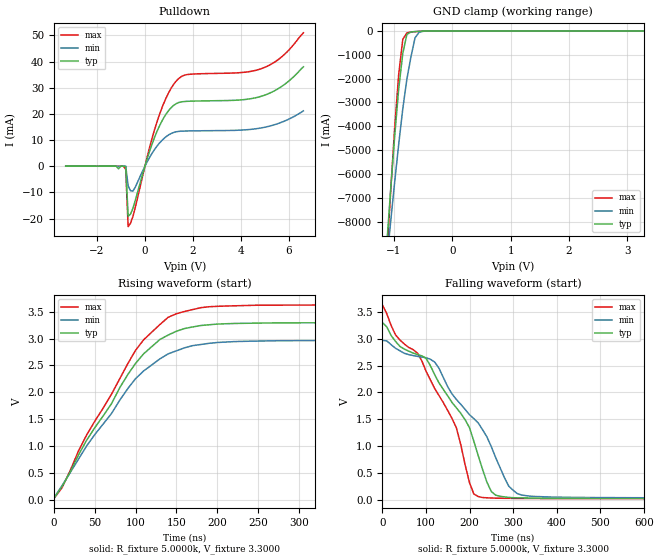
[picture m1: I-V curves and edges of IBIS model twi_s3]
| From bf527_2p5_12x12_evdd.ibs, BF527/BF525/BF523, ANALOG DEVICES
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|   Model ptwi400kv123
[Model]   twi_s3
Model_type I/O_open_drain
Polarity   Non-Inverting
Enable   Active-Low
Vinl =   0.9900V
Vinh =   2.3100V
Vmeas =  1.6500V
Cref =   50.0000pF
Rref =   5.0000k
Vref =   3.3000V
C_comp   7.1300pF   6.4200pF   7.8500pF
[Temperature Range]   25.0000   0.1250k   0.0
[Voltage Range]   3.3000V   2.9700V   3.6300V
[Pullup Reference]   3.3000V   2.9700V   3.6300V
[Pulldown Reference]   0.0V   0.0V   0.0V
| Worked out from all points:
|   slope of the pulldown table from 0 to 0.495 V, typ, clamps not added: 37.7 ohm
|   GND clamp passes 1 mA (typ) near -0.44 V on its own axis
|   rising waveform, R_fixture 5.0000k, V_fixture 3.3000: 20-80 % time 80.6ns typ, 84.1ns min, 80.7ns max; typ from 0.021 V to 3.3 V
|   falling waveform, R_fixture 5.0000k, V_fixture 3.3000: 20-80 % time 127ns typ, 135ns min, 138ns max; typ from 3.3 V to 0.021 V
[Pulldown]
|Voltage   I(typ)   I(min)   I(max)
-3.3V     0A         0A         0A
-900mV    0A         0A         0A
-800mV    -100uA     0A         -1.16mA
-700mV    -19.11mA   -7.5mA     -23.08mA
-500mV    -16.06mA   -9.49mA    -19.19mA
500mV     13.25mA    7.66mA     16.88mA
900mV     20.2mA     11.43mA    26.48mA
1.3V      23.91mA    13.17mA    32.53mA
1.8V      24.83mA    13.48mA    35.09mA
4.9V      26.9mA     14.74mA    37.48mA
5.7V      30.53mA    16.84mA    41.86mA
6.6V      38mA       21.16mA    51mA
[GND_clamp]
|Voltage   I(typ)   I(min)   I(max)
-3.3V     -90.22A    -67.03A    -109.2A
-1.13V    -9.149A    -9.8A      -9.77A
-1.06V    -6.738A    -8.067A    -6.84A
-990mV    -4.45A     -6.376A    -4.101A
-920mV    -2.435A    -4.756A    -1.825A
-850mV    -942.6mA   -3.267A    -350.3mA
-780mV    -143.7mA   -2.02A     -77.09mA
-710mV    -40.25mA   -1.083A    -45.36mA
-640mV    -20.51mA   -284.6mA   -28.77mA
-570mV    -9.991mA   -53.76mA   -15.59mA
-500mV    -3.489mA   -11.54mA   -6.229mA
3.28V     9.245nA    33.22nA    22.11nA
[Ramp]
| variable   typ   min   max
dV/dt_r  1.9668/80.8522n   1.7623/84.3593n   2.1657/80.9872n
dV/dt_f  1.9673/0.1273u   1.7618/0.1350u   2.1662/0.1385u
R_load = 5.0000k
[Rising Waveform]
R_fixture= 5.0000k
V_fixture= 3.3000
V_fixture_min= 2.9700
V_fixture_max= 3.6300
L_fixture= 0.0H
C_fixture= 0.0F
|time   V(typ)   V(min)   V(max)
0s        20.94mV    31.89mV    18.58mV
10.1ns    246.2mV    262.5mV    224.4mV
40.4ns    1.114V     1.007V     1.212V
100ns     2.538V     2.254V     2.782V
130ns     2.986V     2.625V     3.265V
140ns     3.067V     2.717V     3.398V
160ns     3.188V     2.829V     3.506V
190ns     3.258V     2.913V     3.594V
280ns     3.294V     2.962V     3.624V
1us       3.299V     2.969V     3.628V
[Falling Waveform]
R_fixture= 5.0000k
V_fixture= 3.3000
V_fixture_min= 2.9700
V_fixture_max= 3.6300
L_fixture= 0.0H
C_fixture= 0.0F
|time   V(typ)   V(min)   V(max)
0s        3.3V       2.969V     3.629V
30.3ns    2.948V     2.821V     3.07V
120ns     2.331V     2.565V     2.074V
160ns     1.81V      1.969V     1.511V
200ns     1.341V     1.583V     314.6mV
220ns     821.3mV    1.431V     58.01mV
250ns     152.2mV    987.7mV    31.92mV
290ns     42.14mV    253mV      25.46mV
320ns     33.15mV    86.25mV    23.15mV
1us       21.19mV    32.72mV    18.68mV
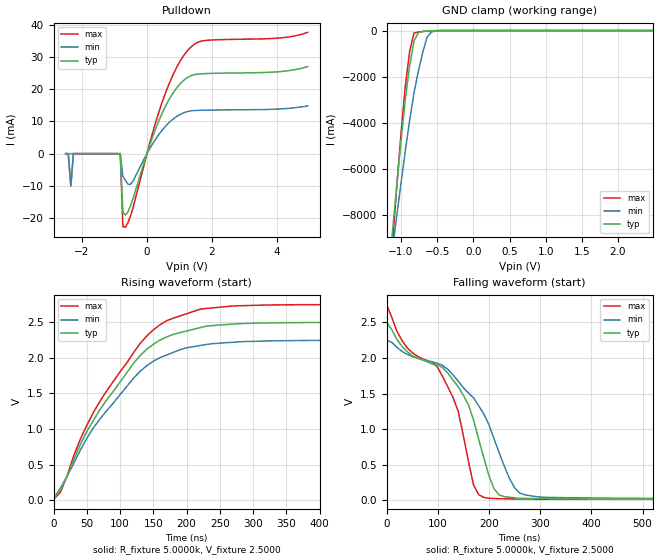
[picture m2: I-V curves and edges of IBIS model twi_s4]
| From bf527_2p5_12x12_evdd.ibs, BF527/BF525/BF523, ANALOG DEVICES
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[Model]   twi_s4
Model_type I/O_open_drain
Polarity   Non-Inverting
Enable   Active-Low
Vinl =   0.7500V
Vinh =   1.7500V
Vmeas =  1.2500V
Cref =   50.0000pF
Rref =   5.0000k
Vref =   2.5000V
C_comp   7.1300pF   6.4200pF   7.8500pF
[Temperature Range]   25.0000   0.1250k   0.0
[Voltage Range]   2.5000V   2.2500V   2.7500V
[Pullup Reference]   2.5000V   2.2500V   2.7500V
[Pulldown Reference]   0.0V   0.0V   0.0V
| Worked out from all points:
|   slope of the pulldown table from 0 to 0.375 V, typ, clamps not added: 36 ohm
|   GND clamp passes 1 mA (typ) near -0.43 V on its own axis
|   rising waveform, R_fixture 5.0000k, V_fixture 2.5000: 20-80 % time 99.5ns typ, 102ns min, 102ns max; typ from 0.016 V to 2.5 V
|   falling waveform, R_fixture 5.0000k, V_fixture 2.5000: 20-80 % time 134ns typ, 106ns min, 125ns max; typ from 2.5 V to 0.016 V
[Pulldown]
|Voltage   I(typ)   I(min)   I(max)
-2.5V     0A         0A         0A
-2.42V    0A         0A         0A
-2.34V    0A         -10mA      -10mA
-2.26V    0A         0A         0A
-820mV    0A         0A         -100uA
-740mV    -18.24mA   -7mA       -22.61mA
-660mV    -19.07mA   -8.3mA     -22.8mA
-500mV    -16.06mA   -9.49mA    -19.19mA
460mV     12.37mA    7.169mA    15.73mA
1.26V     23.69mA    13.08mA    32.09mA
1.74V     24.8mA     13.47mA    35.01mA
4.94V     27.02mA    14.81mA    37.62mA
[GND_clamp]
|Voltage   I(typ)   I(min)   I(max)
-2.5V     -59.97A    -45.67A    -72.09A
-1.12V    -8.799A    -9.551A    -9.345A
-1.06V    -6.738A    -8.067A    -6.84A
-1V       -4.765A    -6.614A    -4.473A
-940mV    -2.968A    -5.209A    -2.401A
-880mV    -1.51A     -3.883A    -891.6mA
-820mV    -449.6mA   -2.695A    -106.2mA
-760mV    -91.03mA   -1.757A    -63.86mA
-640mV    -20.51mA   -284.6mA   -28.77mA
-580mV    -11.24mA   -67.34mA   -17.26mA
-520mV    -4.937mA   -17.93mA   -8.448mA
2.48V     854.5pA    19.73nA    1.171nA
[Ramp]
| variable   typ   min   max
dV/dt_r  1.4899/99.7831n   1.3349/0.1019u   1.6410/0.1023u
dV/dt_f  1.4904/0.1344u   1.3346/0.1063u   1.6415/0.1257u
R_load = 5.0000k
[Rising Waveform]
R_fixture= 5.0000k
V_fixture= 2.5000
V_fixture_min= 2.2500
V_fixture_max= 2.7500
L_fixture= 0.0H
C_fixture= 0.0F
|time   V(typ)   V(min)   V(max)
0s        15.84mV    24.09mV    14.05mV
10.1ns    137.6mV    167.7mV    109.1mV
40.4ns    784.7mV    707.3mV    861.3mV
60.61ns   1.132V     1.027V     1.245V
130ns     2.031V     1.811V     2.201V
150ns     2.19V      1.953V     2.394V
170ns     2.294V     2.04V      2.522V
220ns     2.423V     2.173V     2.682V
350ns     2.494V     2.241V     2.745V
1us       2.499V     2.249V     2.749V
[Falling Waveform]
R_fixture= 5.0000k
V_fixture= 2.5000
V_fixture_min= 2.2500
V_fixture_max= 2.7500
L_fixture= 0.0H
C_fixture= 0.0F
|time   V(typ)   V(min)   V(max)
0s        2.5V       2.249V     2.75V
40.4ns    2.088V     2.051V     2.141V
90.91ns   1.91V      1.941V     1.936V
120ns     1.784V     1.837V     1.59V
140ns     1.596V     1.674V     1.25V
170ns     1.129V     1.439V     212.9mV
190ns     595.7mV    1.214V     40.34mV
220ns     75.56mV    667.9mV    23.3mV
270ns     26.68mV    78.13mV    18.21mV
1us       15.99mV    24.66mV    14.12mV
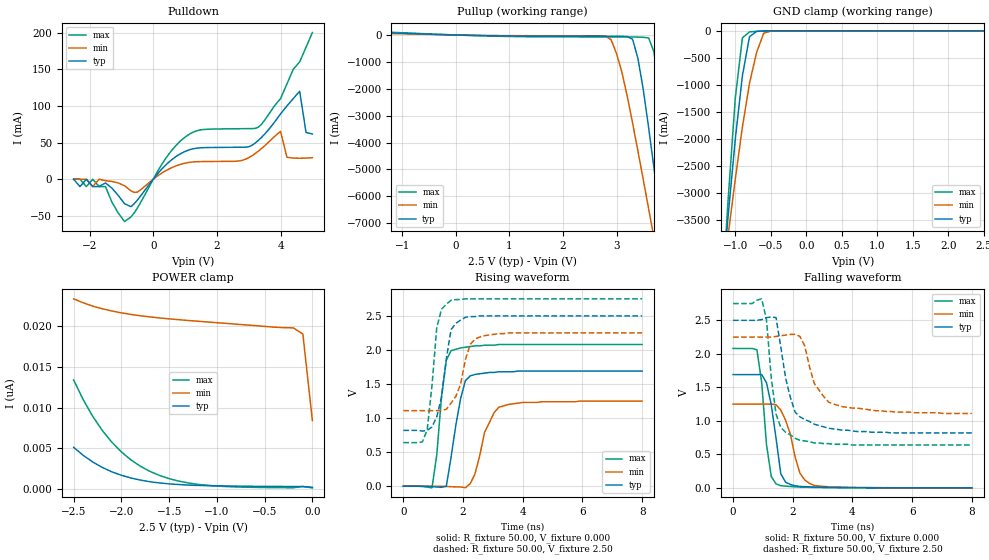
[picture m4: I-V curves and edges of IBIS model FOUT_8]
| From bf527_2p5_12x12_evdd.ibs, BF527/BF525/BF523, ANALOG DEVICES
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|   Model prw0408swcdg_3v_25
[Model]   FOUT_8
Model_type   I/O
Polarity   Non-Inverting
Enable   Active-Low
Vinl =   0.70V
Vinh =   1.70V
Vmeas =   1.20V
Cref =  50.00pF
Rref =   1.00M
Vref =  0.000V
C_comp   4.63pF   4.17pF   5.09pF
[Temperature Range]   25.00   0.12k   -40.00
[Voltage Range]   2.50V   2.25V   2.75V
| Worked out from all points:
|   slope of the pulldown table from 0 to 0.375 V, typ, clamps not added: 20.2 ohm
|   slope of the pullup table from 0 to 0.375 V, typ, clamps not added: 20.2 ohm
|   GND clamp passes 1 mA (typ) near -0.53 V on its own axis
|   rising waveform, R_fixture 50.00, V_fixture 0.000: 20-80 % time 392ps typ, 513ps min, 278ps max; typ from 0 V to 1.69 V
|   rising waveform, R_fixture 50.00, V_fixture 2.50: 20-80 % time 354ps typ, 422ps min, 263ps max; typ from 0.82 V to 2.5 V
|   falling waveform, R_fixture 50.00, V_fixture 0.000: 20-80 % time 336ps typ, 452ps min, 269ps max; typ from 1.69 V to 0 V
|   falling waveform, R_fixture 50.00, V_fixture 2.50: 20-80 % time 484ps typ, 633ps min, 317ps max; typ from 2.5 V to 0.82 V
[Pulldown]
| voltage   I(typ)   I(min)   I(max)
-2.5V     0A         0A         0A
-1.5V     -5mA       -2mA       -10mA
-900mV    -33.4mA    -9mA       -57.7mA
-500mV    -28.54mA   -17.58mA   -39.44mA
1V        37.88mA    21.94mA    57.43mA
3V        44.3mA     29.45mA    69.02mA
3.4V      56.94mA    41.79mA    74.82mA
4V        89.19mA    65.21mA    110mA
4.2V      100mA      30.03mA    130mA
4.6V      120mA      28.64mA    160mA
4.8V      63.78mA    28.87mA    180mA
5V        61.71mA    29.39mA    200mA
[Pullup]
| voltage   I(typ)   I(min)   I(max)
-2.5V     14.45mA    2.51mA     46.73mA
2.8V      -46.96mA   -42.82mA   -72.11mA
2.9V      -47.06mA   -180mA     -72.23mA
3V        -47.56mA   -690mA     -72.33mA
3.3V      -160mA     -3.28A     -74.26mA
3.4V      -880mA     -4.32A     -79.19mA
3.6V      -3.46A     -6.47A     -110mA
3.7V      -4.96A     -7.56A     -640mA
3.8V      -6.5A      -8.65A     -2.2A
4V        -9.62A     -10.85A    -6.34A
4.2V      -12.77A    -13.07A    -10.72A
5V        -25.49A    -21.97A    -28.57A
[GND_clamp]
| voltage   I(typ)   I(min)   I(max)
-2.5V     -25.44A    -19.16A    -34.1A
-1.2V     -4.91A     -4.82A     -5.19A
-1.1V     -3.41A     -3.77A     -3.1A
-1V       -2A        -2.74A     -1.24A
-900mV    -830mA     -1.78A     -130mA
-800mV    -110mA     -970mA     -19.37mA
-700mV    -10.09mA   -400mA     -9.85mA
-600mV    -2.6mA     -44.25mA   -3.52mA
-500mV    -460uA     -4.5mA     -550uA
2.5V      210pA      19.84nA    120pA
[POWER_clamp]
| voltage   I(typ)   I(min)   I(max)
-2.5V     5.13nA     23.39nA    13.42nA
-2.4V     4.14nA     22.91nA    10.99nA
-2.3V     3.32nA     22.5nA     8.94nA
-2.1V     2.11nA     21.9nA     5.76nA
-1.9V     1.35nA     21.47nA    3.58nA
-1.7V     890pA      21.17nA    2.16nA
-1.5V     630pA      20.93nA    1.27nA
-1.2V     440pA      20.64nA    570pA
-800mV    350pA      20.28nA    250pA
-200mV    300pA      19.82nA    150pA
-100mV    300pA      19.07nA    310pA
0V        210pA      8.42nA     140pA
[Ramp]
| variable   typ   min   max
dV/dt_r   1.02/0.29n   0.75/0.49n   1.25/0.20n
dV/dt_f   1.01/0.40n   0.68/0.63n   1.27/0.26n
R_load = 50.00
[Rising Waveform]
R_fixture = 50.00
V_fixture = 0.000
V_fixture_min = 0.000
V_fixture_max = 0.000
L_fixture = 0.000H
C_fixture = 0.000F
| time   V(typ)   V(min)   V(max)
0s        0V         0V         0V
960ps     -5.87mV    84.62uV    -23.63mV
1.12ns    -11.28mV   -450uV     460mV
1.44ns    1.11mV     -3mV       1.85V
1.6ns     430mV      -7.38mV    1.99V
1.92ns    1.29V      -11.13mV   2.03V
2.24ns    1.62V      36.47mV    2.05V
2.72ns    1.66V      790mV      2.07V
3.2ns     1.68V      1.16V      2.08V
8ns       1.69V      1.25V      2.08V
[Rising Waveform]
R_fixture = 50.00
V_fixture = 2.50
V_fixture_min = 2.25
V_fixture_max = 2.75
L_fixture = 0.000H
C_fixture = 0.000F
| time   V(typ)   V(min)   V(max)
0s        820mV      1.11V      640mV
640ps     810mV      1.11V      650mV
800ps     820mV      1.11V      830mV
1.12ns    1.02V      1.11V      2.33V
1.28ns    1.31V      1.11V      2.6V
1.6ns     2.3V       1.22V      2.73V
1.92ns    2.44V      1.5V       2.74V
2.24ns    2.49V      2.08V      2.75V
2.56ns    2.5V       2.19V      2.75V
8ns       2.5V       2.25V      2.75V
[Falling Waveform]
R_fixture = 50.00
V_fixture = 0.000
V_fixture_min = 0.000
V_fixture_max = 0.000
L_fixture = 0.000H
C_fixture = 0.000F
| time   V(typ)   V(min)   V(max)
0s        1.69V      1.25V      2.08V
800ps     1.69V      1.25V      2.06V
960ps     1.69V      1.25V      1.57V
1.12ns    1.57V      1.25V      650mV
1.44ns    740mV      1.24V      59.97mV
1.6ns     210mV      1.16V      31.55mV
1.76ns    84mV       1.01V      25.52mV
2.24ns    21.61mV    220mV      11.78mV
2.72ns    11.89mV    35.54mV    5.86mV
8ns       29.53uV    150uV      -15.18uV
[Falling Waveform]
R_fixture = 50.00
V_fixture = 2.50
V_fixture_min = 2.25
V_fixture_max = 2.75
L_fixture = 0.000H
C_fixture = 0.000F
| time   V(typ)   V(min)   V(max)
0s        2.5V       2.25V      2.75V
960ps     2.51V      2.25V      2.82V
1.12ns    2.54V      2.25V      2.51V
1.28ns    2.55V      2.25V      1.64V
1.44ns    2.54V      2.26V      1.1V
1.76ns    1.64V      2.28V      830mV
2.08ns    1.13V      2.29V      740mV
2.72ns    950mV      1.56V      670mV
3.2ns     890mV      1.28V      660mV
8ns       820mV      1.11V      640mV
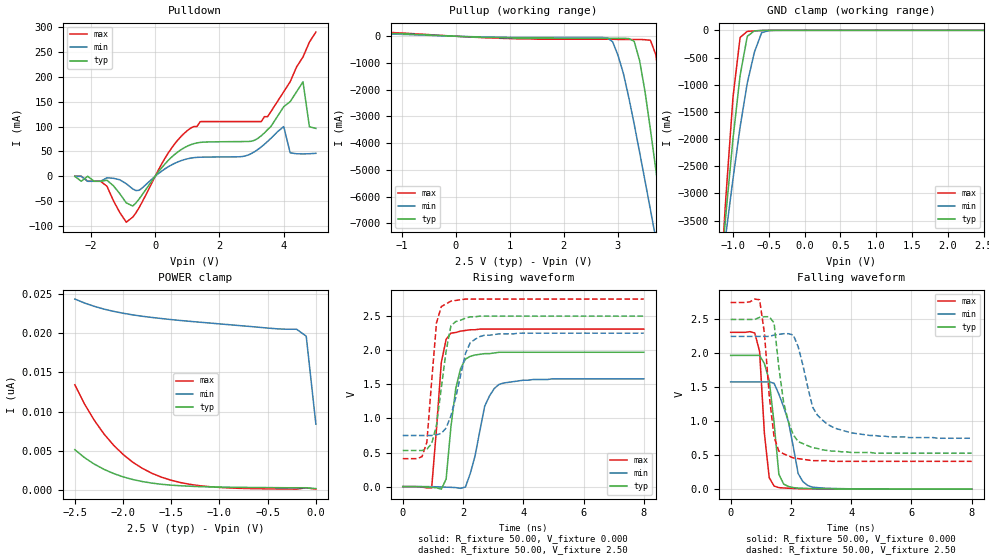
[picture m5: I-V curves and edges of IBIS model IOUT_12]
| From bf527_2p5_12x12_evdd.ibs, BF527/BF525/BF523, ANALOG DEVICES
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|   Model prw0812swcdg_25
[Model]   IOUT_12
Model_type   I/O
Polarity   Non-Inverting
Enable   Active-Low
Vinl =   0.70V
Vinh =   1.70V
Vmeas =   1.20V
Cref =  50.00pF
Rref =   1.00M
Vref =  0.000V
C_comp   4.38pF   3.94pF   4.82pF
[Temperature Range]   25.00   0.12k   -40.00
[Voltage Range]   2.50V   2.25V   2.75V
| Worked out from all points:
|   slope of the pulldown table from 0 to 0.375 V, typ, clamps not added: 12.6 ohm
|   slope of the pullup table from 0 to 0.375 V, typ, clamps not added: 12.7 ohm
|   GND clamp passes 1 mA (typ) near -0.53 V on its own axis
|   rising waveform, R_fixture 50.00, V_fixture 0.000: 20-80 % time 336ps typ, 492ps min, 245ps max; typ from 0 V to 1.97 V
|   rising waveform, R_fixture 50.00, V_fixture 2.50: 20-80 % time 363ps typ, 474ps min, 257ps max; typ from 0.53 V to 2.5 V
|   falling waveform, R_fixture 50.00, V_fixture 0.000: 20-80 % time 277ps typ, 490ps min, 224ps max; typ from 1.97 V to 0 V
|   falling waveform, R_fixture 50.00, V_fixture 2.50: 20-80 % time 452ps typ, 646ps min, 289ps max; typ from 2.5 V to 0.53 V
[Pulldown]
| voltage   I(typ)   I(min)   I(max)
-2.5V     0A         0A         0A
-1.5V     -8mA       -3mA       -20mA
-900mV    -53.4mA    -15mA      -92.3mA
-500mV    -45.67mA   -28.14mA   -63.1mA
900mV     57.24mA    33.39mA    86.24mA
1.4V      68.13mA    38.37mA    110mA
3.3V      81.44mA    59.05mA    110mA
4V        140mA      100mA      170mA
4.2V      150mA      47.22mA    190mA
4.6V      190mA      45mA       240mA
4.8V      99.62mA    45.37mA    270mA
5V        96.33mA    46.19mA    290mA
[Pullup]
| voltage   I(typ)   I(min)   I(max)
-2.5V     20.7mA     3.18mA     65.52mA
2.8V      -74.78mA   -59.76mA   -110mA
2.9V      -74.93mA   -200mA     -110mA
3V        -75.48mA   -710mA     -120mA
3.3V      -190mA     -3.29A     -120mA
3.4V      -910mA     -4.34A     -120mA
3.6V      -3.49A     -6.49A     -150mA
3.7V      -4.99A     -7.58A     -690mA
3.8V      -6.53A     -8.67A     -2.24A
4V        -9.65A     -10.87A    -6.38A
4.2V      -12.8A     -13.09A    -10.76A
5V        -25.52A    -21.99A    -28.62A
[GND_clamp]
| voltage   I(typ)   I(min)   I(max)
-2.5V     -25.44A    -19.16A    -34.1A
-1.2V     -4.91A     -4.82A     -5.19A
-1.1V     -3.41A     -3.77A     -3.1A
-1V       -2A        -2.74A     -1.24A
-900mV    -830mA     -1.78A     -130mA
-800mV    -110mA     -970mA     -19.37mA
-700mV    -10.09mA   -400mA     -9.85mA
-600mV    -2.6mA     -44.25mA   -3.52mA
-500mV    -460uA     -4.5mA     -550uA
2.5V      210pA      20.5nA     120pA
[POWER_clamp]
| voltage   I(typ)   I(min)   I(max)
-2.5V     5.16nA     24.33nA    13.42nA
-2.4V     4.16nA     23.83nA    10.99nA
-2.3V     3.34nA     23.41nA    8.94nA
-2.1V     2.14nA     22.77nA    5.76nA
-1.9V     1.37nA     22.32nA    3.58nA
-1.7V     910pA      21.99nA    2.16nA
-1.5V     650pA      21.72nA    1.27nA
-1.2V     460pA      21.38nA    570pA
-800mV    370pA      20.96nA    250pA
-200mV    320pA      20.49nA    150pA
-100mV    320pA      19.61nA    310pA
0V        210pA      8.42nA     140pA
[Ramp]
| variable   typ   min   max
dV/dt_r   1.18/0.27n   0.95/0.49n   1.39/0.17n
dV/dt_f   1.18/0.36n   0.90/0.60n   1.41/0.22n
R_load = 50.00
[Rising Waveform]
R_fixture = 50.00
V_fixture = 0.000
V_fixture_min = 0.000
V_fixture_max = 0.000
L_fixture = 0.000H
C_fixture = 0.000F
| time   V(typ)   V(min)   V(max)
0s        0V         0V         0V
960ps     -11.1mV    -530uV     -18.16mV
1.28ns    -37.34mV   -5.35mV    1.82V
1.44ns    110mV      -8.35mV    2.16V
1.6ns     880mV      -10.44mV   2.25V
1.76ns    1.44V      -14.37mV   2.26V
2.08ns    1.87V      -6.33mV    2.29V
2.72ns    1.95V      1.18V      2.31V
3.2ns     1.97V      1.5V       2.31V
8ns       1.97V      1.58V      2.31V
[Rising Waveform]
R_fixture = 50.00
V_fixture = 2.50
V_fixture_min = 2.25
V_fixture_max = 2.75
L_fixture = 0.000H
C_fixture = 0.000F
| time   V(typ)   V(min)   V(max)
0s        530mV      750mV      410mV
640ps     530mV      750mV      440mV
800ps     550mV      750mV      650mV
960ps     630mV      750mV      1.55V
1.12ns    900mV      760mV      2.4V
1.28ns    1.45V      780mV      2.64V
1.6ns     2.36V      1.04V      2.72V
2.08ns    2.47V      1.95V      2.75V
2.56ns    2.5V       2.2V       2.75V
8ns       2.5V       2.25V      2.75V
[Falling Waveform]
R_fixture = 50.00
V_fixture = 0.000
V_fixture_min = 0.000
V_fixture_max = 0.000
L_fixture = 0.000H
C_fixture = 0.000F
| time   V(typ)   V(min)   V(max)
0s        1.97V      1.58V      2.31V
800ps     1.97V      1.58V      2.3V
960ps     1.97V      1.58V      2.03V
1.28ns    1.6V       1.58V      170mV
1.44ns    980mV      1.56V      46.05mV
1.6ns     220mV      1.4V       22.46mV
1.76ns    74.15mV    1.21V      17.52mV
2.24ns    15.88mV    230mV      7.2mV
2.56ns    10.73mV    53.97mV    4.87mV
8ns       41.75uV    120uV      8.89uV
[Falling Waveform]
R_fixture = 50.00
V_fixture = 2.50
V_fixture_min = 2.25
V_fixture_max = 2.75
L_fixture = 0.000H
C_fixture = 0.000F
| time   V(typ)   V(min)   V(max)
0s        2.5V       2.25V      2.75V
960ps     2.53V      2.25V      2.79V
1.12ns    2.54V      2.25V      2.3V
1.44ns    2.45V      2.27V      770mV
1.6ns     1.79V      2.28V      560mV
1.92ns    990mV      2.29V      490mV
2.24ns    700mV      2.1V       450mV
2.72ns    610mV      1.21V      420mV
3.36ns    560mV      920mV      410mV
8ns       530mV      750mV      410mV
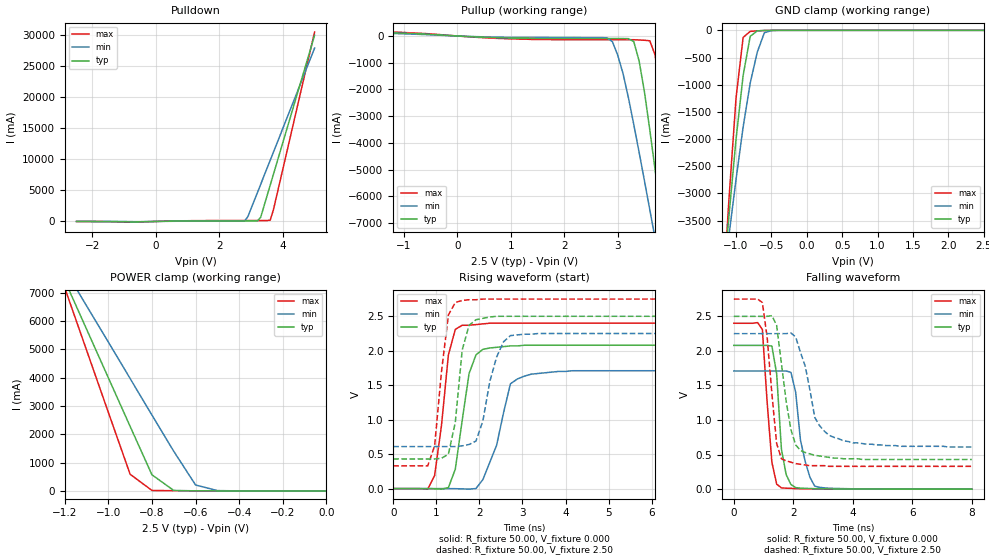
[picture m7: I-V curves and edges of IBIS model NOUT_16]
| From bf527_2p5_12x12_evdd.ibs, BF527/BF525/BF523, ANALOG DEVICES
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|   Model prw1216hcdg_25
[Model]   NOUT_16
Model_type   I/O
Polarity   Non-Inverting
Enable   Active-Low
Vinl =   0.70V
Vinh =   1.70V
Vmeas =   1.20V
Cref =  50.00pF
Rref =   1.00M
Vref =  0.000V
C_comp   4.60pF   4.14pF   5.06pF
[Temperature Range]   25.00   0.12k   -40.00
[Voltage Range]   2.50V   2.25V   2.75V
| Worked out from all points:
|   slope of the pulldown table from 0 to 0.375 V, typ, clamps not added: 10.1 ohm
|   slope of the pullup table from 0 to 0.375 V, typ, clamps not added: 9.95 ohm
|   GND clamp passes 1 mA (typ) near -0.53 V on its own axis
|   POWER clamp passes 1 mA (typ) near -0.53 V on its own axis
|   rising waveform, R_fixture 50.00, V_fixture 0.000: 20-80 % time 288ps typ, 446ps min, 253ps max; typ from 0 V to 2.08 V
|   rising waveform, R_fixture 50.00, V_fixture 2.50: 20-80 % time 234ps typ, 352ps min, 242ps max; typ from 0.43 V to 2.5 V
|   falling waveform, R_fixture 50.00, V_fixture 0.000: 20-80 % time 230ps typ, 353ps min, 244ps max; typ from 2.08 V to 0 V
|   falling waveform, R_fixture 50.00, V_fixture 2.50: 20-80 % time 409ps typ, 570ps min, 307ps max; typ from 2.5 V to 0.43 V
[Pulldown]
| voltage   I(typ)   I(min)   I(max)
-2.5V     0A         -10mA      0A
-900mV    -66.7mA    -19mA      -120mA
900mV     71.55mA    41.73mA    110mA
2.8V      87.33mA    98.46mA    140mA
2.9V      87.43mA    800mA      140mA
3.2V      100mA      4.66A      140mA
3.3V      650mA      5.95A      140mA
3.6V      5.81A      9.81A      200mA
3.7V      7.53A      11.1A      1.82A
5V        29.92A     27.88A     30.44A
[Pullup]
| voltage   I(typ)   I(min)   I(max)
-2.5V     190mA      170mA      220mA
2.8V      -94.19mA   -73.06mA   -140mA
2.9V      -94.42mA   -210mA     -140mA
3V        -95.02mA   -720mA     -140mA
3.3V      -210mA     -3.31A     -140mA
3.4V      -930mA     -4.35A     -150mA
3.6V      -3.51A     -6.5A      -180mA
3.7V      -5.01A     -7.59A     -710mA
3.8V      -6.55A     -8.69A     -2.27A
4V        -9.67A     -10.89A    -6.41A
4.2V      -12.82A    -13.1A     -10.79A
5V        -25.54A    -22A       -28.64A
[GND_clamp]
| voltage   I(typ)   I(min)   I(max)
-2.5V     -25.44A    -19.15A    -34.1A
-1.2V     -4.91A     -4.82A     -5.19A
-1.1V     -3.41A     -3.77A     -3.1A
-1V       -2A        -2.74A     -1.24A
-900mV    -830mA     -1.78A     -130mA
-800mV    -110mA     -970mA     -19.32mA
-700mV    -10.06mA   -400mA     -9.82mA
-600mV    -2.59mA    -44.19mA   -3.51mA
-500mV    -470uA     -4.47mA    -560uA
2.5V      200pA      14.35uA    -5.72uA
[POWER_clamp]
| voltage   I(typ)   I(min)   I(max)
-2.5V     29.82A     24.6A      35.79A
-1.2V     7.44A      7.83A      7.18A
-1.1V     5.72A      6.54A      4.98A
-900mV    2.28A      3.97A      590mA
-800mV    570mA      2.68A      17mA
-700mV    17.04mA    1.4A       7.09mA
-600mV    2.37mA     210mA      2.78mA
-500mV    470uA      11.87mA    550uA
0V        200pA      8.28nA     120pA
[Ramp]
| variable   typ   min   max
dV/dt_r   1.25/0.26n   1.03/0.41n   1.44/0.20n
dV/dt_f   1.24/0.32n   0.98/0.54n   1.45/0.23n
R_load = 50.00
[Rising Waveform]
R_fixture = 50.00
V_fixture = 0.000
V_fixture_min = 0.000
V_fixture_max = 0.000
L_fixture = 0.000H
C_fixture = 0.000F
| time   V(typ)   V(min)   V(max)
0s        0V         0V         0V
960ps     -2.03mV    71.69uV    190mV
1.28ns    14.14mV    -470uV     1.94V
1.44ns    280mV      -1.24mV    2.31V
1.6ns     990mV      -4.12mV    2.37V
1.76ns    1.67V      -8.14mV    2.37V
1.92ns    1.94V      1.06mV     2.38V
2.72ns    2.07V      1.52V      2.4V
2.88ns    2.07V      1.59V      2.4V
8ns       2.08V      1.71V      2.4V
[Rising Waveform]
R_fixture = 50.00
V_fixture = 2.50
V_fixture_min = 2.25
V_fixture_max = 2.75
L_fixture = 0.000H
C_fixture = 0.000F
| time   V(typ)   V(min)   V(max)
0s        430mV      610mV      330mV
800ps     430mV      610mV      330mV
960ps     430mV      610mV      620mV
1.28ns    500mV      610mV      2.52V
1.44ns    960mV      610mV      2.7V
1.6ns     2.01V      620mV      2.73V
1.92ns    2.45V      690mV      2.74V
2.4ns     2.5V       1.91V      2.75V
2.72ns    2.5V       2.22V      2.75V
8ns       2.5V       2.25V      2.75V
[Falling Waveform]
R_fixture = 50.00
V_fixture = 0.000
V_fixture_min = 0.000
V_fixture_max = 0.000
L_fixture = 0.000H
C_fixture = 0.000F
| time   V(typ)   V(min)   V(max)
0s        2.08V      1.71V      2.4V
960ps     2.08V      1.71V      2.31V
1.28ns    2.07V      1.71V      390mV
1.44ns    1.67V      1.71V      73.07mV
1.6ns     580mV      1.71V      18.68mV
1.92ns    67.03mV    1.69V      11.66mV
2.08ns    22.45mV    1.4V       8.16mV
2.24ns    14.51mV    710mV      6.11mV
2.72ns    7.13mV     43.43mV    3.12mV
8ns       74.95uV    170uV      29.6uV
[Falling Waveform]
R_fixture = 50.00
V_fixture = 2.50
V_fixture_min = 2.25
V_fixture_max = 2.75
L_fixture = 0.000H
C_fixture = 0.000F
| time   V(typ)   V(min)   V(max)
0s        2.5V       2.25V      2.75V
960ps     2.5V       2.25V      2.7V
1.12ns    2.5V       2.25V      2.2V
1.44ns    2.37V      2.25V      660mV
1.6ns     1.82V      2.25V      440mV
1.92ns    860mV      2.26V      390mV
2.24ns    560mV      1.98V      360mV
2.72ns    490mV      1.04V      340mV
3.2ns     460mV      780mV      330mV
8ns       430mV      610mV      330mV
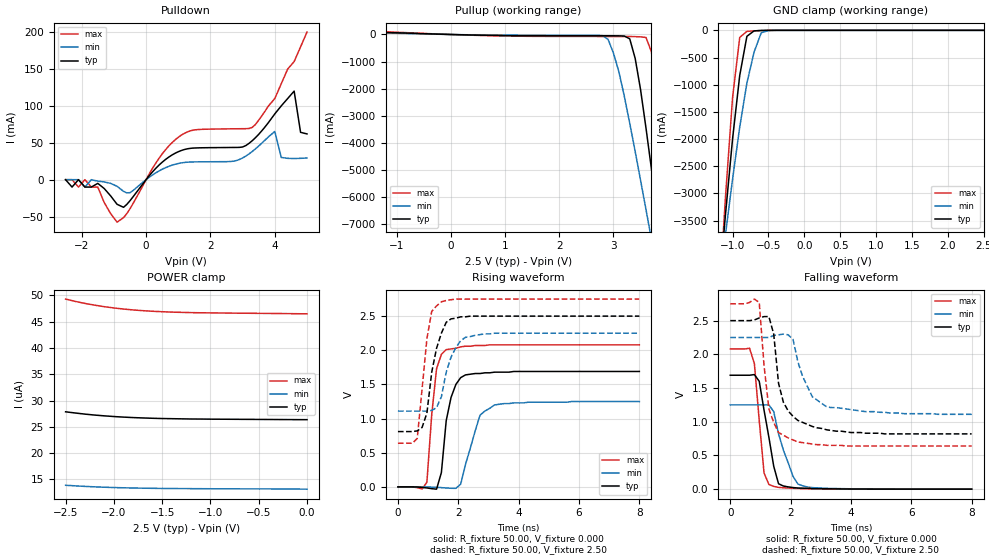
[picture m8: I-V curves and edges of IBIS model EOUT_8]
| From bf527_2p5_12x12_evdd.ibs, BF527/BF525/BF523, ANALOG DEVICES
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|   Model prwd0408swcdg_25
[Model]   EOUT_8
Model_type   I/O
Polarity   Non-Inverting
Enable   Active-Low
Vinl =   0.70V
Vinh =   1.70V
Vmeas =   1.20V
Cref =  50.00pF
Rref =   1.00M
Vref =  0.000V
C_comp   4.97pF   4.47pF   5.46pF
[Temperature Range]   25.00   0.12k   -40.00
[Voltage Range]   2.50V   2.25V   2.75V
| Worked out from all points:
|   slope of the pulldown table from 0 to 0.375 V, typ, clamps not added: 20.2 ohm
|   slope of the pullup table from 0 to 0.375 V, typ, clamps not added: 20.2 ohm
|   GND clamp passes 1 mA (typ) near -0.52 V on its own axis
|   rising waveform, R_fixture 50.00, V_fixture 0.000: 20-80 % time 328ps typ, 489ps min, 248ps max; typ from 0 V to 1.69 V
|   rising waveform, R_fixture 50.00, V_fixture 2.50: 20-80 % time 398ps typ, 451ps min, 305ps max; typ from 0.81 V to 2.5 V
|   falling waveform, R_fixture 50.00, V_fixture 0.000: 20-80 % time 389ps typ, 519ps min, 247ps max; typ from 1.69 V to 0 V
|   falling waveform, R_fixture 50.00, V_fixture 2.50: 20-80 % time 458ps typ, 646ps min, 347ps max; typ from 2.5 V to 0.82 V
[Pulldown]
| voltage   I(typ)   I(min)   I(max)
-2.5V     0A         0A         0A
-1.5V     -5mA       -2mA       -10mA
-900mV    -33.4mA    -9mA       -57.6mA
-500mV    -28.54mA   -17.58mA   -39.44mA
1V        37.88mA    21.95mA    57.44mA
3V        44.32mA    29.46mA    69.07mA
3.4V      56.97mA    41.8mA     74.87mA
4V        89.22mA    65.31mA    110mA
4.2V      100mA      30.14mA    130mA
4.6V      120mA      28.7mA     160mA
4.8V      64.18mA    28.92mA    180mA
5V        61.98mA    29.43mA    200mA
[Pullup]
| voltage   I(typ)   I(min)   I(max)
-2.5V     14.7mA     2.55mA     48.45mA
2.8V      -46.97mA   -42.82mA   -72.12mA
2.9V      -47.08mA   -180mA     -72.23mA
3V        -47.58mA   -690mA     -72.35mA
3.3V      -160mA     -3.28A     -74.28mA
3.4V      -880mA     -4.32A     -79.2mA
3.6V      -3.46A     -6.47A     -110mA
3.7V      -4.96A     -7.56A     -640mA
3.8V      -6.5A      -8.65A     -2.2A
4V        -9.62A     -10.85A    -6.34A
4.2V      -12.77A    -13.07A    -10.72A
5V        -25.49A    -21.97A    -28.57A
[GND_clamp]
| voltage   I(typ)   I(min)   I(max)
-2.5V     -25.44A    -19.16A    -34.1A
-1.2V     -4.91A     -4.82A     -5.19A
-1.1V     -3.41A     -3.77A     -3.1A
-1V       -2A        -2.74A     -1.24A
-900mV    -830mA     -1.78A     -130mA
-800mV    -110mA     -970mA     -19.39mA
-700mV    -10.1mA    -400mA     -9.87mA
-600mV    -2.61mA    -44.25mA   -3.54mA
-500mV    -470uA     -4.51mA    -570uA
2.5V      26.35uA    13.17uA    46.42uA
[POWER_clamp]
| voltage   I(typ)   I(min)   I(max)
-2.5V     27.85uA    13.87uA    49.3uA
-2.4V     27.62uA    13.76uA    48.86uA
-2.3V     27.41uA    13.66uA    48.47uA
-2.2V     27.23uA    13.57uA    48.14uA
-2.1V     27.08uA    13.5uA     47.85uA
-1.9V     26.84uA    13.39uA    47.4uA
-1.7V     26.68uA    13.32uA    47.09uA
-1.5V     26.57uA    13.27uA    46.89uA
-1.2V     26.48uA    13.23uA    46.72uA
-700mV    26.42uA    13.19uA    46.61uA
-400mV    26.39uA    13.18uA    46.57uA
0V        26.35uA    13.13uA    46.49uA
[Ramp]
| variable   typ   min   max
dV/dt_r   1.02/0.30n   0.75/0.46n   1.25/0.19n
dV/dt_f   1.01/0.42n   0.68/0.62n   1.27/0.27n
R_load = 50.00
[Rising Waveform]
R_fixture = 50.00
V_fixture = 0.000
V_fixture_min = 0.000
V_fixture_max = 0.000
L_fixture = 0.000H
C_fixture = 0.000F
| time   V(typ)   V(min)   V(max)
0s        0V         0V         0V
960ps     -15.34mV   -520uV     68.93mV
1.12ns    -25.66mV   -2.74mV    1.06V
1.28ns    -33.04mV   -6.06mV    1.73V
1.44ns    210mV      -10.69mV   1.94V
1.6ns     970mV      -15.58mV   2.01V
2.08ns    1.6V       40.25mV    2.05V
2.72ns    1.66V      1.05V      2.07V
3.2ns     1.68V      1.2V       2.08V
8ns       1.69V      1.25V      2.08V
[Rising Waveform]
R_fixture = 50.00
V_fixture = 2.50
V_fixture_min = 2.25
V_fixture_max = 2.75
L_fixture = 0.000H
C_fixture = 0.000F
| time   V(typ)   V(min)   V(max)
0s        810mV      1.11V      640mV
640ps     820mV      1.11V      710mV
800ps     870mV      1.11V      1.43V
960ps     1.08V      1.11V      2.17V
1.12ns    1.68V      1.12V      2.57V
1.44ns    2.25V      1.32V      2.71V
1.6ns     2.41V      1.68V      2.73V
1.76ns    2.46V      1.9V       2.74V
2.24ns    2.49V      2.19V      2.75V
8ns       2.5V       2.25V      2.75V
[Falling Waveform]
R_fixture = 50.00
V_fixture = 0.000
V_fixture_min = 0.000
V_fixture_max = 0.000
L_fixture = 0.000H
C_fixture = 0.000F
| time   V(typ)   V(min)   V(max)
0s        1.69V      1.25V      2.08V
640ps     1.69V      1.25V      2.09V
800ps     1.7V       1.25V      1.86V
960ps     1.6V       1.25V      1.02V
1.12ns    1.17V      1.25V      240mV
1.28ns    770mV      1.25V      69.99mV
1.44ns    340mV      1.15V      40.72mV
1.6ns     80.27mV    820mV      26.49mV
2.24ns    17.16mV    76.38mV    9.98mV
8ns       15.32uV    120uV      9.13uV
[Falling Waveform]
R_fixture = 50.00
V_fixture = 2.50
V_fixture_min = 2.25
V_fixture_max = 2.75
L_fixture = 0.000H
C_fixture = 0.000F
| time   V(typ)   V(min)   V(max)
0s        2.5V       2.25V      2.75V
960ps     2.54V      2.25V      2.77V
1.12ns    2.56V      2.25V      1.83V
1.28ns    2.56V      2.25V      1.19V
1.44ns    2.3V       2.28V      990mV
1.6ns     1.57V      2.29V      840mV
2.08ns    1.08V      2.22V      730mV
2.72ns    930mV      1.37V      670mV
3.2ns     880mV      1.22V      650mV
8ns       820mV      1.11V      640mV
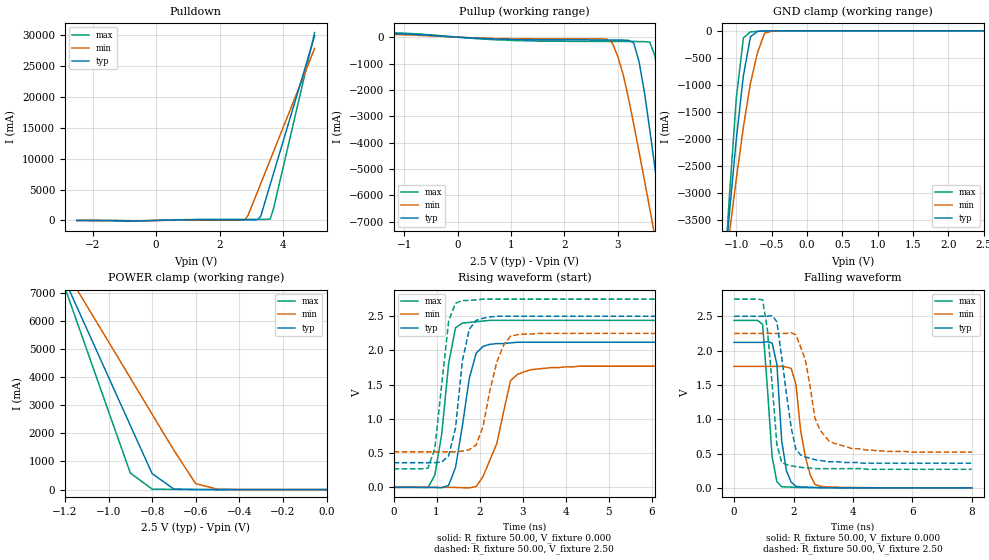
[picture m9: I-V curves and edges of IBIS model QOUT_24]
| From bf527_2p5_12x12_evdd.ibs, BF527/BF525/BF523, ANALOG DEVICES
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|   Model prw1624cdg_25
[Model]   QOUT_24
Model_type   I/O
Polarity   Non-Inverting
Enable   Active-Low
Vinl =   0.70V
Vinh =   1.70V
Vmeas =   1.20V
Cref =  50.00pF
Rref =   1.00M
Vref =  0.000V
C_comp   4.43pF   3.98pF   4.87pF
[Temperature Range]   25.00   0.12k   -40.00
[Voltage Range]   2.50V   2.25V   2.75V
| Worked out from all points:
|   slope of the pulldown table from 0 to 0.375 V, typ, clamps not added: 8.41 ohm
|   slope of the pullup table from 0 to 0.375 V, typ, clamps not added: 8.85 ohm
|   GND clamp passes 1 mA (typ) near -0.53 V on its own axis
|   POWER clamp passes 1 mA (typ) near -0.53 V on its own axis
|   rising waveform, R_fixture 50.00, V_fixture 0.000: 20-80 % time 331ps typ, 459ps min, 282ps max; typ from 0 V to 2.12 V
|   rising waveform, R_fixture 50.00, V_fixture 2.50: 20-80 % time 269ps typ, 382ps min, 256ps max; typ from 0.36 V to 2.5 V
|   falling waveform, R_fixture 50.00, V_fixture 0.000: 20-80 % time 242ps typ, 357ps min, 240ps max; typ from 2.12 V to 0 V
|   falling waveform, R_fixture 50.00, V_fixture 2.50: 20-80 % time 417ps typ, 502ps min, 284ps max; typ from 2.5 V to 0.36 V
[Pulldown]
| voltage   I(typ)   I(min)   I(max)
-2.5V     0A         -10mA      0A
-900mV    -80.1mA    -23mA      -140mA
1.1V      95.08mA    54.68mA    150mA
2.8V      100mA      110mA      170mA
2.9V      100mA      810mA      170mA
3.2V      120mA      4.67A      170mA
3.3V      670mA      5.96A      170mA
3.6V      5.83A      9.82A      230mA
3.7V      7.55A      11.11A     1.85A
5V        29.94A     27.89A     30.47A
[Pullup]
| voltage   I(typ)   I(min)   I(max)
-2.5V     220mA      190mA      250mA
2.8V      -110mA     -80.42mA   -160mA
2.9V      -110mA     -220mA     -160mA
3V        -110mA     -730mA     -160mA
3.3V      -220mA     -3.31A     -160mA
3.4V      -940mA     -4.36A     -170mA
3.6V      -3.52A     -6.51A     -190mA
3.7V      -5.02A     -7.6A      -730mA
3.8V      -6.56A     -8.69A     -2.28A
4V        -9.68A     -10.89A    -6.43A
4.2V      -12.83A    -13.11A    -10.8A
5V        -25.55A    -22.01A    -28.66A
[GND_clamp]
| voltage   I(typ)   I(min)   I(max)
-2.5V     -25.44A    -19.15A    -34.1A
-1.2V     -4.91A     -4.82A     -5.19A
-1.1V     -3.41A     -3.77A     -3.1A
-1V       -2A        -2.74A     -1.24A
-900mV    -830mA     -1.78A     -130mA
-800mV    -110mA     -970mA     -19.31mA
-700mV    -10.05mA   -400mA     -9.81mA
-600mV    -2.58mA    -44.19mA   -3.5mA
-500mV    -450uA     -4.46mA    -550uA
2.5V      190pA      11.03uA    100pA
[POWER_clamp]
| voltage   I(typ)   I(min)   I(max)
-2.5V     29.82A     24.6A      35.79A
-1.2V     7.44A      7.83A      7.18A
-1.1V     5.72A      6.54A      4.98A
-900mV    2.28A      3.97A      590mA
-800mV    570mA      2.68A      16.99mA
-700mV    17.03mA    1.4A       7.08mA
-600mV    2.36mA     210mA      2.77mA
-500mV    460uA      11.86mA    530uA
0V        190pA      8.27nA     120pA
[Ramp]
| variable   typ   min   max
dV/dt_r   1.27/0.28n   1.06/0.42n   1.46/0.21n
dV/dt_f   1.29/0.31n   1.04/0.50n   1.49/0.22n
R_load = 50.00
[Rising Waveform]
R_fixture = 50.00
V_fixture = 0.000
V_fixture_min = 0.000
V_fixture_max = 0.000
L_fixture = 0.000H
C_fixture = 0.000F
| time   V(typ)   V(min)   V(max)
0s        0V         0V         0V
960ps     -2.72mV    64.09uV    180mV
1.12ns    -7.44mV    -160uV     780mV
1.28ns    29.29mV    -550uV     1.81V
1.44ns    290mV      -1.69mV    2.33V
1.6ns     900mV      -5.82mV    2.4V
1.92ns    1.96V      11.48mV    2.42V
2.4ns     2.1V       640mV      2.44V
2.88ns    2.12V      1.65V      2.44V
8ns       2.12V      1.77V      2.44V
[Rising Waveform]
R_fixture = 50.00
V_fixture = 2.50
V_fixture_min = 2.25
V_fixture_max = 2.75
L_fixture = 0.000H
C_fixture = 0.000F
| time   V(typ)   V(min)   V(max)
0s        360mV      520mV      270mV
800ps     360mV      520mV      280mV
960ps     360mV      520mV      570mV
1.28ns    460mV      520mV      2.43V
1.44ns    870mV      520mV      2.69V
1.6ns     1.85V      530mV      2.73V
1.92ns    2.44V      620mV      2.74V
2.4ns     2.5V       1.83V      2.75V
2.72ns    2.5V       2.21V      2.75V
8ns       2.5V       2.25V      2.75V
[Falling Waveform]
R_fixture = 50.00
V_fixture = 0.000
V_fixture_min = 0.000
V_fixture_max = 0.000
L_fixture = 0.000H
C_fixture = 0.000F
| time   V(typ)   V(min)   V(max)
0s        2.12V      1.77V      2.44V
960ps     2.12V      1.77V      2.38V
1.28ns    2.11V      1.77V      450mV
1.44ns    1.8V       1.77V      89.67mV
1.6ns     690mV      1.77V      16.06mV
1.76ns    250mV      1.76V      13.23mV
2.08ns    21.54mV    1.51V      6.95mV
2.4ns     10.69mV    450mV      4.14mV
2.72ns    6.21mV     49.81mV    2.43mV
8ns       31.07uV    100uV      5.71uV
[Falling Waveform]
R_fixture = 50.00
V_fixture = 2.50
V_fixture_min = 2.25
V_fixture_max = 2.75
L_fixture = 0.000H
C_fixture = 0.000F
| time   V(typ)   V(min)   V(max)
0s        2.5V       2.25V      2.75V
960ps     2.5V       2.25V      2.74V
1.12ns    2.5V       2.25V      2.31V
1.44ns    2.42V      2.25V      630mV
1.6ns     1.91V      2.25V      370mV
1.92ns    880mV      2.26V      320mV
2.24ns    480mV      2.05V      300mV
2.72ns    410mV      1.02V      280mV
3.2ns     380mV      680mV      280mV
8ns       360mV      520mV      270mV
